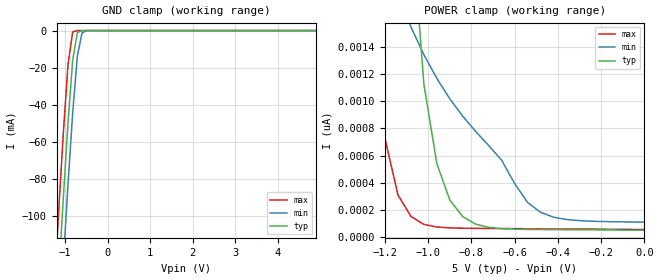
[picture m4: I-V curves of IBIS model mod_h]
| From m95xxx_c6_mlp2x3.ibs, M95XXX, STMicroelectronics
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|   Model mod_h
[Model]   mod_h
Model_type Input
Vinl   =   1.250V
Vinh   =   3.750V
C_comp   2.119pF   2.024pF   2.324pF
[Temperature Range]  25.0000   85.0000   -40.0000
[Voltage Range]   5.0000V   4.5000V   5.5000V
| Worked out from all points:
|   GND clamp passes 1 mA (typ) near -0.70 V on its own axis
[GND_clamp]
|Voltage   I(typ)   I(min)   I(max)
-5V       -1.764A    -1.796A    -1.733A
-1.26V    -176.7mA   -211.6mA   -141.2mA
-1.15V    -132.7mA   -167.5mA   -97.27mA
-1.04V    -89.88mA   -124.3mA   -55.14mA
-930mV    -49.58mA   -82.71mA   -18.16mA
-820mV    -15.87mA   -44.29mA   -757uA
-710mV    -1.068mA   -13.78mA   -5.45uA
-600mV    -23.1uA    -1.246mA   -36.27nA
-490mV    -459.2nA   -51.76uA   -242.2pA
4.9V      10.56pA    60.08pA    10.13pA
[POWER_clamp]
|Voltage   I(typ)   I(min)   I(max)
-4.98V    12.15uA    11.29uA    15.58uA
-1.26V    23nA       2.414nA    1.802nA
-1.2V     11.01nA    2.068nA    725.9pA
-1.14V    5.144nA    1.785nA    310.5pA
-1.08V    2.39nA     1.546nA    152.3pA
-1.02V    1.125nA    1.342nA    93.17pA
-960mV    540.6pA    1.167nA    74.33pA
-900mV    272.4pA    1.017nA    67.75pA
-840mV    150.2pA    888.6pA    65.33pA
-720mV    71.6pA     673.4pA    63.6pA
-480mV    55.75pA    182.4pA    61.05pA
0V        50.61pA    110.1pA    56pA
